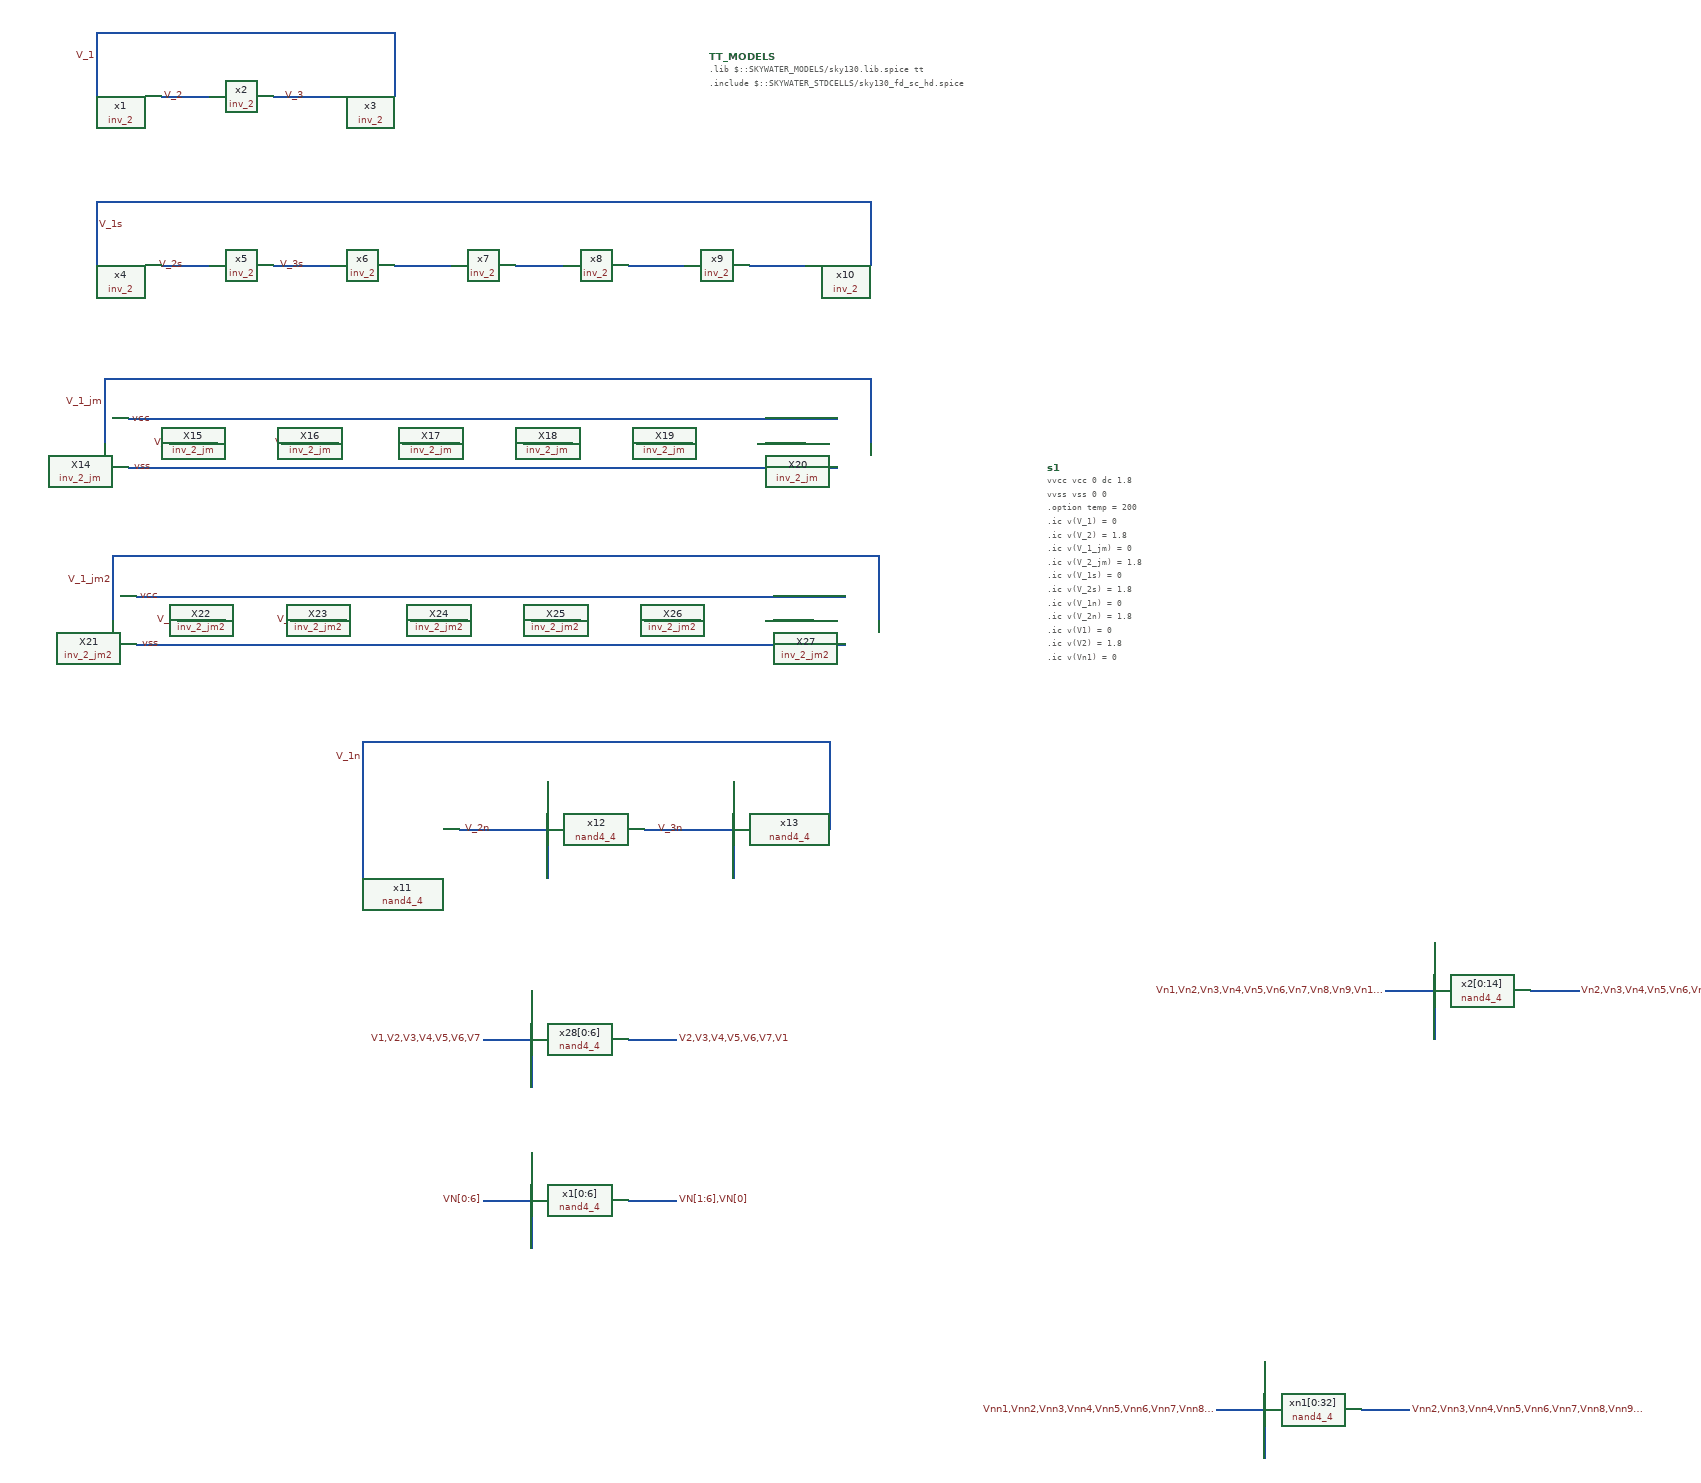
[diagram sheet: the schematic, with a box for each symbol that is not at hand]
v {xschem version=3.4.2 file_version=1.2
}
G {}
K {}
V {}
S {}
E {}
B 2 1710 -830 2510 -430 {flags=graph
y1=-0.082
y2=2
ypos1=0
ypos2=2
divy=5
subdivy=1
unity=1
x1=2.92488e-09
x2=4.26706e-09
divx=5
subdivx=1
node=v_1_jm2
color=7
dataset=-1
unitx=1
logx=0
logy=0
}
N 640 -760 700 -760 {
lab=V_2}
N 780 -760 850 -760 {
lab=V_3}
N 930 -840 930 -760 {
lab=V_1}
N 560 -840 930 -840 {
lab=V_1}
N 560 -840 560 -760 {
lab=V_1}
N 640 -550 700 -550 {
lab=V_2s}
N 780 -550 850 -550 {
lab=V_3s}
N 560 -630 930 -630 {
lab=V_1s}
N 560 -630 560 -550 {
lab=V_1s}
N 1080 -550 1140 -550 {
lab=#net1}
N 1220 -550 1290 -550 {
lab=#net2}
N 930 -550 1000 -550 {
lab=#net3}
N 930 -630 1370 -630 {
lab=V_1s}
N 1370 -550 1440 -550 {
lab=#net4}
N 1370 -630 1520 -630 {
lab=V_1s}
N 1520 -630 1520 -550 {
lab=V_1s}
N 1350 90 1350 130 {
lab=V_3n}
N 1350 130 1350 170 {
lab=V_3n}
N 1350 170 1350 210 {
lab=V_3n}
N 890 90 890 130 {
lab=V_1n}
N 890 130 890 170 {
lab=V_1n}
N 890 170 890 210 {
lab=V_1n}
N 1120 90 1120 130 {
lab=V_2n}
N 1120 130 1120 170 {
lab=V_2n}
N 1120 170 1120 210 {
lab=V_2n}
N 1010 150 1120 150 {
lab=V_2n}
N 1240 150 1350 150 {
lab=V_3n}
N 1470 40 1470 150 {
lab=V_1n}
N 890 40 1470 40 {
lab=V_1n}
N 890 40 890 90 {
lab=V_1n}
N 650 -330 710 -330 {
lab=V_2_jm}
N 790 -330 860 -330 {
lab=V_3_jm}
N 570 -410 570 -330 {
lab=V_1_jm}
N 1090 -330 1150 -330 {
lab=#net5}
N 1230 -330 1300 -330 {
lab=#net6}
N 1380 -330 1440 -330 {
lab=#net7}
N 940 -330 1010 -330 {
lab=#net8}
N 600 -360 1480 -360 {
lab=vcc}
N 600 -300 1480 -300 {
lab=vss}
N 1520 -410 1520 -330 {
lab=V_1_jm}
N 570 -410 1520 -410 {
lab=V_1_jm}
N 660 -110 720 -110 {
lab=V_2_jm2}
N 800 -110 870 -110 {
lab=V_3_jm2}
N 580 -190 580 -110 {
lab=V_1_jm2}
N 1100 -110 1160 -110 {
lab=#net9}
N 1240 -110 1310 -110 {
lab=#net10}
N 1390 -110 1450 -110 {
lab=#net11}
N 950 -110 1020 -110 {
lab=#net12}
N 610 -140 1490 -140 {
lab=vcc}
N 610 -80 1490 -80 {
lab=vss}
N 1530 -190 1530 -110 {
lab=V_1_jm2}
N 580 -190 1530 -190 {
lab=V_1_jm2}
N 1100 350 1100 390 {
lab=V1,V2,V3,V4,V5,V6,V7}
N 1100 390 1100 430 {
lab=V1,V2,V3,V4,V5,V6,V7}
N 1100 430 1100 470 {
lab=V1,V2,V3,V4,V5,V6,V7}
N 1040 410 1100 410 {
lab=V1,V2,V3,V4,V5,V6,V7}
N 1220 410 1280 410 {
lab=V2,V3,V4,V5,V6,V7,V1}
N 1100 550 1100 590 {
lab=VN[0:6]}
N 1100 590 1100 630 {
lab=VN[0:6]}
N 1100 630 1100 670 {
lab=VN[0:6]}
N 1040 610 1100 610 {
lab=VN[0:6]}
N 1220 610 1280 610 {
lab=VN[1:6],VN[0]}
N 2220 290 2220 330 {
lab=Vn1,Vn2,Vn3,Vn4,Vn5,Vn6,Vn7,Vn8,Vn9,Vn10,Vn11,Vn12,Vn13,Vn14,Vn15}
N 2220 330 2220 370 {
lab=Vn1,Vn2,Vn3,Vn4,Vn5,Vn6,Vn7,Vn8,Vn9,Vn10,Vn11,Vn12,Vn13,Vn14,Vn15}
N 2220 370 2220 410 {
lab=Vn1,Vn2,Vn3,Vn4,Vn5,Vn6,Vn7,Vn8,Vn9,Vn10,Vn11,Vn12,Vn13,Vn14,Vn15}
N 2160 350 2220 350 {
lab=Vn1,Vn2,Vn3,Vn4,Vn5,Vn6,Vn7,Vn8,Vn9,Vn10,Vn11,Vn12,Vn13,Vn14,Vn15}
N 2340 350 2400 350 {
lab=Vn2,Vn3,Vn4,Vn5,Vn6,Vn7,Vn8,Vn9,Vn10,Vn11,Vn12,Vn13,Vn14,Vn15,Vn1}
N 2010 810 2010 850 {
lab=Vnn1,Vnn2,Vnn3,Vnn4,Vnn5,Vnn6,Vnn7,Vnn8,Vnn9,Vnn10,Vnn11,Vnn12,Vnn13,Vnn14,Vnn15,Vnn16,Vnn17,Vnn18,Vnn19,Vnn20,Vnn21,Vnn22,Vnn23,Vnn24,Vnn25,Vnn26,Vnn27,Vnn28,Vnn29,Vnn30,Vnn31,Vnn32,Vnn33}
N 2010 850 2010 890 {
lab=Vnn1,Vnn2,Vnn3,Vnn4,Vnn5,Vnn6,Vnn7,Vnn8,Vnn9,Vnn10,Vnn11,Vnn12,Vnn13,Vnn14,Vnn15,Vnn16,Vnn17,Vnn18,Vnn19,Vnn20,Vnn21,Vnn22,Vnn23,Vnn24,Vnn25,Vnn26,Vnn27,Vnn28,Vnn29,Vnn30,Vnn31,Vnn32,Vnn33}
N 2010 890 2010 930 {
lab=Vnn1,Vnn2,Vnn3,Vnn4,Vnn5,Vnn6,Vnn7,Vnn8,Vnn9,Vnn10,Vnn11,Vnn12,Vnn13,Vnn14,Vnn15,Vnn16,Vnn17,Vnn18,Vnn19,Vnn20,Vnn21,Vnn22,Vnn23,Vnn24,Vnn25,Vnn26,Vnn27,Vnn28,Vnn29,Vnn30,Vnn31,Vnn32,Vnn33}
N 1950 870 2010 870 {
lab=Vnn1,Vnn2,Vnn3,Vnn4,Vnn5,Vnn6,Vnn7,Vnn8,Vnn9,Vnn10,Vnn11,Vnn12,Vnn13,Vnn14,Vnn15,Vnn16,Vnn17,Vnn18,Vnn19,Vnn20,Vnn21,Vnn22,Vnn23,Vnn24,Vnn25,Vnn26,Vnn27,Vnn28,Vnn29,Vnn30,Vnn31,Vnn32,Vnn33}
N 2130 870 2190 870 {
lab=Vnn2,Vnn3,Vnn4,Vnn5,Vnn6,Vnn7,Vnn8,Vnn9,Vnn10,Vnn11,Vnn12,Vnn13,Vnn14,Vnn15,Vnn16,Vnn17,Vnn18,Vnn19,Vnn20,Vnn21,Vnn22,Vnn23,Vnn24,Vnn25,Vnn26,Vnn27,Vnn28,Vnn29,Vnn30,Vnn31,Vnn32,Vnn33,Vnn1}
C {sky130_stdcells/inv_2.sym} 600 -760 0 0 {name=x1 VGND=VSS VNB=VSS VPB=VCC VPWR=VCC prefix=sky130_fd_sc_hd__ }
C {devices/code_shown.sym} 1740 -300 0 0 {name=s1 only_toplevel=false value="vvcc vcc 0 dc 1.8
vvss vss 0 0
.option temp = 200
.ic v(V_1) = 0
.ic v(V_2) = 1.8
.ic v(V_1_jm) = 0
.ic v(V_2_jm) = 1.8
.ic v(V_1s) = 0
.ic v(V_2s) = 1.8
.ic v(V_1n) = 0
.ic v(V_2n) = 1.8
.ic v(V1) = 0
.ic v(V2) = 1.8
.ic v(Vn1) = 0
.ic v(Vn2) = 1.8
.ic v(Vnn1) = 0
.ic v(Vnn2) = 1.8

.control
   tran 50p 100n
   *run
   *write TT_3stage_RO_v1p1.raw
   wrdata /foss/designs/TT_temptodig_ROstudy/TT_3stage_RO_v1p1.txt v(Vnn1)
   plot v(vnn1)
.endc
"}
C {devices/lab_pin.sym} 560 -810 0 0 {name=p1 sig_type=std_logic lab=V_1}
C {devices/lab_pin.sym} 670 -760 1 0 {name=p2 sig_type=std_logic lab=V_2}
C {sky130_stdcells/inv_2.sym} 740 -760 0 0 {name=x2 VGND=VSS VNB=VSS VPB=VCC VPWR=VCC prefix=sky130_fd_sc_hd__ }
C {sky130_stdcells/inv_2.sym} 890 -760 0 0 {name=x3 VGND=VSS VNB=VSS VPB=VCC VPWR=VCC prefix=sky130_fd_sc_hd__ }
C {devices/code.sym} 1320 -810 0 0 {name=TT_MODELS
only_toplevel=true
format="tcleval(@value )"
value=".lib $::SKYWATER_MODELS/sky130.lib.spice tt
.include $::SKYWATER_STDCELLS/sky130_fd_sc_hd.spice
"
spice_ignore=false
place=header}
C {devices/lab_pin.sym} 820 -760 1 0 {name=p3 sig_type=std_logic lab=V_3}
C {devices/lab_pin.sym} 560 -600 0 1 {name=p4 sig_type=std_logic lab=V_1s}
C {devices/lab_pin.sym} 670 -550 1 0 {name=p5 sig_type=std_logic lab=V_2s}
C {devices/lab_pin.sym} 820 -550 1 0 {name=p6 sig_type=std_logic lab=V_3s}
C {sky130_stdcells/inv_2.sym} 600 -550 0 0 {name=x4 VGND=VSS VNB=VSS VPB=VCC VPWR=VCC prefix=sky130_fd_sc_hd__ }
C {sky130_stdcells/inv_2.sym} 740 -550 0 0 {name=x5 VGND=VSS VNB=VSS VPB=VCC VPWR=VCC prefix=sky130_fd_sc_hd__ }
C {sky130_stdcells/inv_2.sym} 890 -550 0 0 {name=x6 VGND=VSS VNB=VSS VPB=VCC VPWR=VCC prefix=sky130_fd_sc_hd__ }
C {sky130_stdcells/inv_2.sym} 1040 -550 0 0 {name=x7 VGND=VSS VNB=VSS VPB=VCC VPWR=VCC prefix=sky130_fd_sc_hd__ }
C {sky130_stdcells/inv_2.sym} 1180 -550 0 0 {name=x8 VGND=VSS VNB=VSS VPB=VCC VPWR=VCC prefix=sky130_fd_sc_hd__ }
C {sky130_stdcells/inv_2.sym} 1330 -550 0 0 {name=x9 VGND=VSS VNB=VSS VPB=VCC VPWR=VCC prefix=sky130_fd_sc_hd__ }
C {sky130_stdcells/inv_2.sym} 1480 -550 0 0 {name=x10 VGND=VSS VNB=VSS VPB=VCC VPWR=VCC prefix=sky130_fd_sc_hd__ }
C {sky130_stdcells/nand4_4.sym} 950 150 0 0 {name=x11 VGND=VSS VNB=VSS VPB=VCC VPWR=VCC prefix=sky130_fd_sc_hd__ }
C {devices/lab_pin.sym} 890 60 0 0 {name=p7 sig_type=std_logic lab=V_1n}
C {devices/lab_pin.sym} 1050 150 1 0 {name=p8 sig_type=std_logic lab=V_2n}
C {devices/lab_pin.sym} 1290 150 1 0 {name=p9 sig_type=std_logic lab=V_3n}
C {sky130_stdcells/nand4_4.sym} 1180 150 0 0 {name=x12 VGND=VSS VNB=VSS VPB=VCC VPWR=VCC prefix=sky130_fd_sc_hd__ }
C {sky130_stdcells/nand4_4.sym} 1410 150 0 0 {name=x13 VGND=VSS VNB=VSS VPB=VCC VPWR=VCC prefix=sky130_fd_sc_hd__ }
C {devices/lab_pin.sym} 570 -380 0 0 {name=p10 sig_type=std_logic lab=V_1_jm}
C {devices/lab_pin.sym} 680 -330 1 0 {name=p11 sig_type=std_logic lab=V_2_jm}
C {devices/lab_pin.sym} 830 -330 1 0 {name=p12 sig_type=std_logic lab=V_3_jm}
C {inv_2_jm.sym} 530 -330 0 0 {name=X14}
C {inv_2_jm.sym} 670 -330 0 0 {name=X15}
C {inv_2_jm.sym} 820 -330 0 0 {name=X16}
C {devices/lab_pin.sym} 630 -360 1 0 {name=p13 sig_type=std_logic lab=vcc}
C {devices/lab_pin.sym} 630 -300 3 0 {name=p14 sig_type=std_logic lab=vss}
C {inv_2_jm.sym} 970 -330 0 0 {name=X17}
C {inv_2_jm.sym} 1110 -330 0 0 {name=X18}
C {inv_2_jm.sym} 1260 -330 0 0 {name=X19}
C {inv_2_jm.sym} 1400 -330 0 0 {name=X20}
C {devices/lab_pin.sym} 580 -160 0 0 {name=p15 sig_type=std_logic lab=V_1_jm2}
C {devices/lab_pin.sym} 690 -110 1 0 {name=p16 sig_type=std_logic lab=V_2_jm2}
C {devices/lab_pin.sym} 840 -110 1 0 {name=p17 sig_type=std_logic lab=V_3_jm2}
C {inv_2_jm2.sym} 540 -110 0 0 {name=X21}
C {inv_2_jm2.sym} 680 -110 0 0 {name=X22}
C {inv_2_jm2.sym} 830 -110 0 0 {name=X23}
C {devices/lab_pin.sym} 640 -140 1 0 {name=p18 sig_type=std_logic lab=vcc}
C {devices/lab_pin.sym} 640 -80 3 0 {name=p19 sig_type=std_logic lab=vss}
C {inv_2_jm2.sym} 980 -110 0 0 {name=X24}
C {inv_2_jm2.sym} 1120 -110 0 0 {name=X25}
C {inv_2_jm2.sym} 1270 -110 0 0 {name=X26}
C {inv_2_jm2.sym} 1410 -110 0 0 {name=X27}
C {sky130_stdcells/nand4_4.sym} 1160 410 0 0 {name=x28[0:6] VGND=VSS VNB=VSS VPB=VCC VPWR=VCC prefix=sky130_fd_sc_hd__ }
C {devices/lab_pin.sym} 1040 410 0 0 {name=p20 sig_type=std_logic lab=V1,V2,V3,V4,V5,V6,V7}
C {devices/lab_pin.sym} 1280 410 0 1 {name=p21 sig_type=std_logic lab=V2,V3,V4,V5,V6,V7,V1}
C {sky130_stdcells/nand4_4.sym} 1160 610 0 0 {name=x1[0:6] VGND=VSS VNB=VSS VPB=VCC VPWR=VCC prefix=sky130_fd_sc_hd__ }
C {devices/lab_pin.sym} 1040 610 0 0 {name=p22 sig_type=std_logic lab=VN[0:6]}
C {devices/lab_pin.sym} 1280 610 0 1 {name=p23 sig_type=std_logic lab=VN[1:6],VN[0]}
C {sky130_stdcells/nand4_4.sym} 2280 350 0 0 {name=x2[0:14] VGND=VSS VNB=VSS VPB=VCC VPWR=VCC prefix=sky130_fd_sc_hd__ }
C {devices/lab_pin.sym} 2160 350 0 0 {name=p24 sig_type=std_logic lab=Vn1,Vn2,Vn3,Vn4,Vn5,Vn6,Vn7,Vn8,Vn9,Vn10,Vn11,Vn12,Vn13,Vn14,Vn15}
C {devices/lab_pin.sym} 2400 350 0 1 {name=p25 sig_type=std_logic lab=Vn2,Vn3,Vn4,Vn5,Vn6,Vn7,Vn8,Vn9,Vn10,Vn11,Vn12,Vn13,Vn14,Vn15,Vn1}
C {sky130_stdcells/nand4_4.sym} 2070 870 0 0 {name=xn1[0:32] VGND=VSS VNB=VSS VPB=VCC VPWR=VCC prefix=sky130_fd_sc_hd__ }
C {devices/lab_pin.sym} 1950 870 0 0 {name=p26 sig_type=std_logic lab=Vnn1,Vnn2,Vnn3,Vnn4,Vnn5,Vnn6,Vnn7,Vnn8,Vnn9,Vnn10,Vnn11,Vnn12,Vnn13,Vnn14,Vnn15,Vnn16,Vnn17,Vnn18,Vnn19,Vnn20,Vnn21,Vnn22,Vnn23,Vnn24,Vnn25,Vnn26,Vnn27,Vnn28,Vnn29,Vnn30,Vnn31,Vnn32,Vnn33}
C {devices/lab_pin.sym} 2190 870 0 1 {name=p27 sig_type=std_logic lab=Vnn2,Vnn3,Vnn4,Vnn5,Vnn6,Vnn7,Vnn8,Vnn9,Vnn10,Vnn11,Vnn12,Vnn13,Vnn14,Vnn15,Vnn16,Vnn17,Vnn18,Vnn19,Vnn20,Vnn21,Vnn22,Vnn23,Vnn24,Vnn25,Vnn26,Vnn27,Vnn28,Vnn29,Vnn30,Vnn31,Vnn32,Vnn33,Vnn1}
